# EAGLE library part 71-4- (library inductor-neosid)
TRANSFORMER adjustable filter transformer

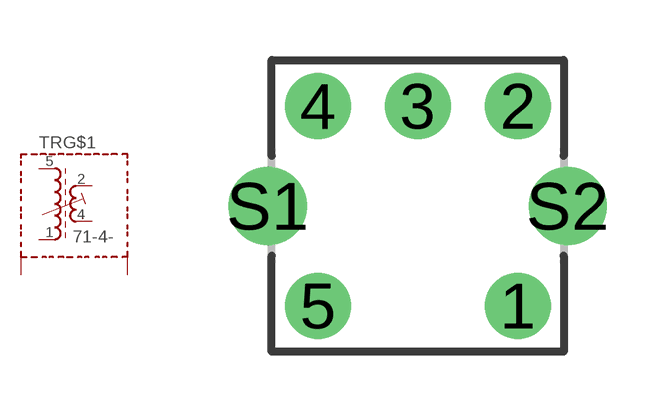
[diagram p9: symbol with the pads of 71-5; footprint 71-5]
Designator prefix TR; gates G$2=SHIELD3 G$1=SMF51-3

## 71-4-5124  [71-5]
1  G$1:E1  pas
2  G$1:A2  pas
4  G$1:E2  pas
5  G$1:A1  pas
S1  G$2:S1  pas
S2  G$2:S2  pas

## 71-4-4215  [71-5]
1  G$1:A2  pas
2  G$1:E1  pas
4  G$1:A1  pas
5  G$1:E2  pas
S1  G$2:S1  pas
S2  G$2:S2  pas

## 71-4-1542  [71-5]
1  G$1:A1  pas
2  G$1:A2  pas
4  G$1:E2  pas
5  G$1:E1  pas
S1  G$2:S1  pas
S2  G$2:S2  pas

## 71-4-2451  [71-5]
1  G$1:E2  pas
2  G$1:A1  pas
4  G$1:E1  pas
5  G$1:A2  pas
S1  G$2:S1  pas
S2  G$2:S2  pas

## 71-4-4251  [71-5]
1  G$1:E2  pas
2  G$1:E1  pas
4  G$1:A1  pas
5  G$1:A2  pas
S1  G$2:S1  pas
S2  G$2:S2  pas

## 71-4-2315  [71-5]
1  G$1:A2  pas
2  G$1:A1  pas
3  G$1:E1  pas
5  G$1:E2  pas
S1  G$2:S1  pas
S2  G$2:S2  pas

## 71-4-5142  [71-5]
1  G$1:E1  pas
2  G$1:E2  pas
4  G$1:A2  pas
5  G$1:A1  pas
S1  G$2:S1  pas
S2  G$2:S2  pas

## 71-4-5412  [71-5]
1  G$1:A2  pas
2  G$1:E2  pas
4  G$1:E1  pas
5  G$1:A1  pas
S1  G$2:S1  pas
S2  G$2:S2  pas

## 71-4-1524  [71-5]
Pads as for 71-5

## 71-4-2143  [71-5]
1  G$1:E1  pas
2  G$1:A1  pas
3  G$1:E2  pas
4  G$1:A2  pas
S1  G$2:S1  pas
S2  G$2:S2  pas

## 71-4-5123  [71-5]
1  G$1:E1  pas
2  G$1:A2  pas
3  G$1:E2  pas
5  G$1:A1  pas
S1  G$2:S1  pas
S2  G$2:S2  pas

## 71-4-5241  [71-5]
1  G$1:E2  pas
2  G$1:E1  pas
4  G$1:A2  pas
5  G$1:A1  pas
S1  G$2:S1  pas
S2  G$2:S2  pas

## 71-4-4512  [71-5]
1  G$1:A2  pas
2  G$1:E2  pas
4  G$1:A1  pas
5  G$1:E1  pas
S1  G$2:S1  pas
S2  G$2:S2  pas

## 71-4-1532  [71-5]
1  G$1:A1  pas
2  G$1:E2  pas
3  G$1:A2  pas
5  G$1:E1  pas
S1  G$2:S1  pas
S2  G$2:S2  pas

## 71-4-3254  [71-5]
2  G$1:E1  pas
3  G$1:A1  pas
4  G$1:E2  pas
5  G$1:A2  pas
S1  G$2:S1  pas
S2  G$2:S2  pas

## 71-4-2415  [71-5]
1  G$1:A2  pas
2  G$1:A1  pas
4  G$1:E1  pas
5  G$1:E2  pas
S1  G$2:S1  pas
S2  G$2:S2  pas

## Footprint 71-5 (pad centres in mm)
RF COIL ASSEMBLY 1 winding, 5 pads, grid 2.5 mm
drill 1.1 round: 1 2.5,-2.5; 2 2.5,2.5; 3 0,2.5; 4 -2.5,2.5; 5 -2.5,-2.5
drill 1.3 round: S1 -3.75,0; S2 3.75,0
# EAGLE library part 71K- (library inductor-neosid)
TRANSFORMER adjustable filter transformer, type K

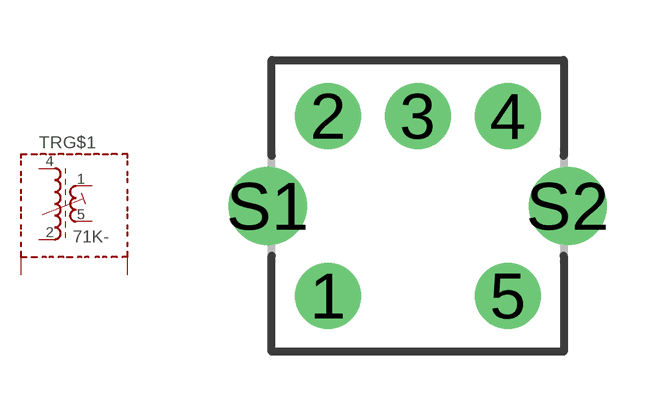
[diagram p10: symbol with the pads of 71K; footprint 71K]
Designator prefix TR; gates G$1=SMF51-3 G$2=SHIELD3

## 71K-4215  [71K]
1  G$1:A2  pas
2  G$1:E1  pas
4  G$1:A1  pas
5  G$1:E2  pas
S1  G$2:S1  pas
S2  G$2:S2  pas

## 71K-1542  [71K]
1  G$1:A1  pas
2  G$1:A2  pas
4  G$1:E2  pas
5  G$1:E1  pas
S1  G$2:S1  pas
S2  G$2:S2  pas

## 71K-2451  [71K]
1  G$1:E2  pas
2  G$1:A1  pas
4  G$1:E1  pas
5  G$1:A2  pas
S1  G$2:S1  pas
S2  G$2:S2  pas

## 71K-4251  [71K]
1  G$1:E2  pas
2  G$1:E1  pas
4  G$1:A1  pas
5  G$1:A2  pas
S1  G$2:S1  pas
S2  G$2:S2  pas

## 71K-2315  [71K]
1  G$1:A2  pas
2  G$1:A1  pas
3  G$1:E1  pas
5  G$1:E2  pas
S1  G$2:S1  pas
S2  G$2:S2  pas

## 71K-5142  [71K]
1  G$1:E1  pas
2  G$1:E2  pas
4  G$1:A2  pas
5  G$1:A1  pas
S1  G$2:S1  pas
S2  G$2:S2  pas

## 71K-5412  [71K]
1  G$1:A2  pas
2  G$1:E2  pas
4  G$1:E1  pas
5  G$1:A1  pas
S1  G$2:S1  pas
S2  G$2:S2  pas

## 71K-1524  [71K]
Pads as for 71K

## 71K-2143  [71K]
1  G$1:E1  pas
2  G$1:A1  pas
3  G$1:E2  pas
4  G$1:A2  pas
S1  G$2:S1  pas
S2  G$2:S2  pas

## 71K-5123  [71K]
1  G$1:E1  pas
2  G$1:A2  pas
3  G$1:E2  pas
5  G$1:A1  pas
S1  G$2:S1  pas
S2  G$2:S2  pas

## 71K-5241  [71K]
1  G$1:E2  pas
2  G$1:E1  pas
4  G$1:A2  pas
5  G$1:A1  pas
S1  G$2:S1  pas
S2  G$2:S2  pas

## 71K-4512  [71K]
1  G$1:A2  pas
2  G$1:E2  pas
4  G$1:A1  pas
5  G$1:E1  pas
S1  G$2:S1  pas
S2  G$2:S2  pas

## 71K-1532  [71K]
1  G$1:A1  pas
2  G$1:E2  pas
3  G$1:A2  pas
5  G$1:E1  pas
S1  G$2:S1  pas
S2  G$2:S2  pas

## 71K-3254  [71K]
2  G$1:E1  pas
3  G$1:A1  pas
4  G$1:E2  pas
5  G$1:A2  pas
S1  G$2:S1  pas
S2  G$2:S2  pas

## 71K-2415  [71K]
1  G$1:A2  pas
2  G$1:A1  pas
4  G$1:E1  pas
5  G$1:E2  pas
S1  G$2:S1  pas
S2  G$2:S2  pas

## Footprint 71K (pad centres in mm)
RF COIL ASSEMBLY 1 winding, 5 pads, grid 2.25 mm
drill 1.1 round: 1 -2.25,-2.25; 2 -2.25,2.25; 3 0,2.25; 4 2.25,2.25; 5 2.25,-2.25
drill 1.3 round: S1 -3.75,0; S2 3.75,0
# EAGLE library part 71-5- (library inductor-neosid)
TRANSFORMER adjustable filter transformer with tap

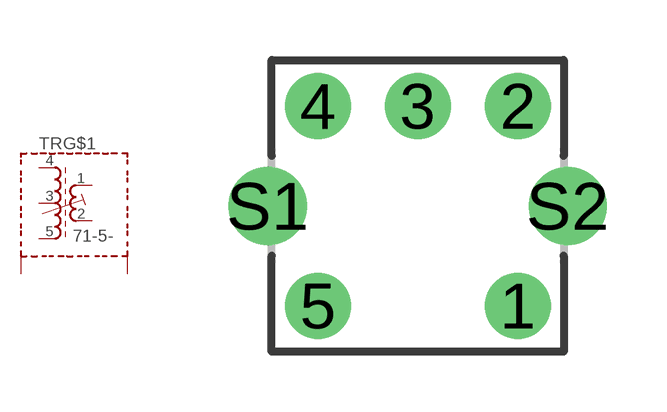
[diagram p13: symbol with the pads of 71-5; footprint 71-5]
Designator prefix TR; gates G$1=SMF51-4 G$2=SHIELD3

## 71-5-45123  [71-5]
1  G$1:A2  pas
2  G$1:E2  pas
3  G$1:Z  pas
4  G$1:A1  pas
5  G$1:E1  pas
S1  G$2:S1  pas
S2  G$2:S2  pas

## 71-5-42153  [71-5]
1  G$1:A2  pas
2  G$1:E1  pas
3  G$1:Z  pas
4  G$1:A1  pas
5  G$1:E2  pas
S1  G$2:S1  pas
S2  G$2:S2  pas

## 71-5-13542  [71-5]
1  G$1:A1  pas
2  G$1:Z  pas
3  G$1:E1  pas
4  G$1:E2  pas
5  G$1:A2  pas
S1  G$2:S1  pas
S2  G$2:S2  pas

## 71-5-43512  [71-5]
1  G$1:E2  pas
2  G$1:Z  pas
3  G$1:E1  pas
4  G$1:A1  pas
5  G$1:A2  pas
S1  G$2:S1  pas
S2  G$2:S2  pas

## 71-5-51423  [71-5]
1  G$1:E1  pas
2  G$1:E2  pas
3  G$1:Z  pas
4  G$1:A2  pas
5  G$1:A1  pas
S1  G$2:S1  pas
S2  G$2:S2  pas

## 71-5-32154  [71-5]
1  G$1:A2  pas
2  G$1:E1  pas
3  G$1:A1  pas
4  G$1:Z  pas
5  G$1:E2  pas
S1  G$2:S1  pas
S2  G$2:S2  pas

## 71-5-15423  [71-5]
1  G$1:A1  pas
2  G$1:E2  pas
3  G$1:Z  pas
4  G$1:A2  pas
5  G$1:E1  pas
S1  G$2:S1  pas
S2  G$2:S2  pas

## 71-5-24153  [71-5]
1  G$1:A2  pas
2  G$1:A1  pas
3  G$1:Z  pas
4  G$1:E1  pas
5  G$1:E2  pas
S1  G$2:S1  pas
S2  G$2:S2  pas

## 71-5-24513  [71-5]
1  G$1:E2  pas
2  G$1:A1  pas
3  G$1:Z  pas
4  G$1:E1  pas
5  G$1:A2  pas
S1  G$2:S1  pas
S2  G$2:S2  pas

## 71-5-42513  [71-5]
1  G$1:E2  pas
2  G$1:E1  pas
3  G$1:Z  pas
4  G$1:A1  pas
5  G$1:A2  pas
S1  G$2:S1  pas
S2  G$2:S2  pas

## 71-5-34153  [71-5]
1  G$1:A2  pas
2  G$1:Z  pas
3  G$1:A1  pas
4  G$1:E1  pas
5  G$1:E2  pas
S1  G$2:S1  pas
S2  G$2:S2  pas

## 71-5-34512  [71-5]
1  G$1:E2  pas
2  G$1:Z  pas
3  G$1:A1  pas
4  G$1:E1  pas
5  G$1:A2  pas
S1  G$2:S1  pas
S2  G$2:S2  pas

## 71-5-41325  [71-5]
1  G$1:E1  pas
2  G$1:E2  pas
3  G$1:A2  pas
4  G$1:A1  pas
5  G$1:Z  pas
S1  G$2:S1  pas
S2  G$2:S2  pas

## 71-5-34152  [71-5]
Pads as for 71-5

## Footprint 71-5 (pad centres in mm)
RF COIL ASSEMBLY 1 winding, 5 pads, grid 2.5 mm
drill 1.1 round: 1 2.5,-2.5; 2 2.5,2.5; 3 0,2.5; 4 -2.5,2.5; 5 -2.5,-2.5
drill 1.3 round: S1 -3.75,0; S2 3.75,0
